VERSION 5.7 ;
BUSBITCHARS "[]" ;
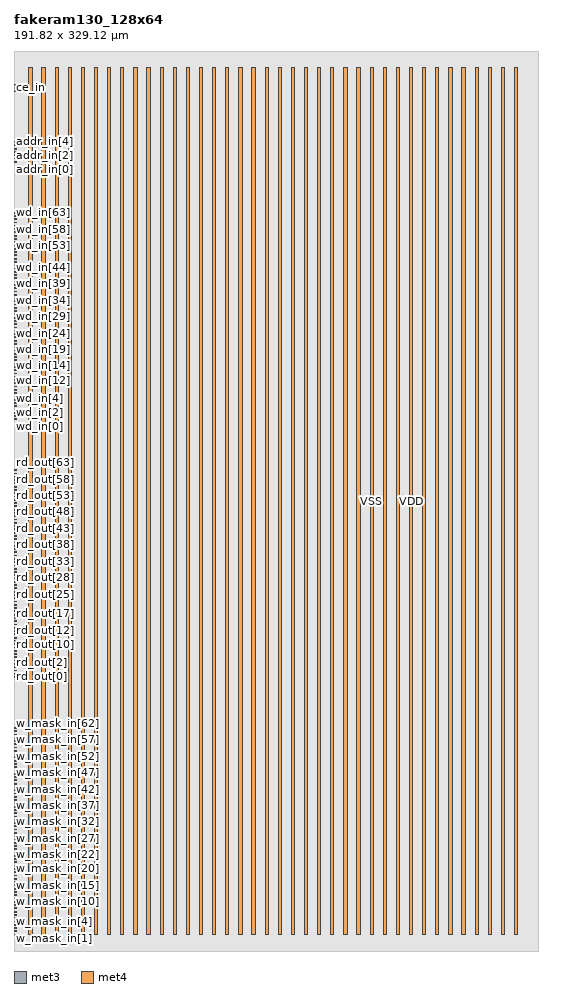
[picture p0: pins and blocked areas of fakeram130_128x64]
MACRO fakeram130_128x64
  FOREIGN fakeram130_128x64 0 0 ;
  SYMMETRY X Y R90 ;
  SIZE 191.820 BY 329.120 ;
  CLASS BLOCK ;
  PIN w_mask_in[0]
    DIRECTION INPUT ;
    USE SIGNAL ;
    SHAPE ABUTMENT ;
    PORT
      LAYER met3 ;
      RECT 0.000 5.850 0.800 6.150 ;
    END
  END w_mask_in[0]
  PIN w_mask_in[1]
    DIRECTION INPUT ;
    USE SIGNAL ;
    SHAPE ABUTMENT ;
    PORT
      LAYER met3 ;
      RECT 0.000 7.050 0.800 7.350 ;
    END
  END w_mask_in[1]
  PIN w_mask_in[2]
    DIRECTION INPUT ;
    USE SIGNAL ;
    SHAPE ABUTMENT ;
    PORT
      LAYER met3 ;
      RECT 0.000 8.250 0.800 8.550 ;
    END
  END w_mask_in[2]
  PIN w_mask_in[3]
    DIRECTION INPUT ;
    USE SIGNAL ;
    SHAPE ABUTMENT ;
    PORT
      LAYER met3 ;
      RECT 0.000 9.450 0.800 9.750 ;
    END
  END w_mask_in[3]
  PIN w_mask_in[4]
    DIRECTION INPUT ;
    USE SIGNAL ;
    SHAPE ABUTMENT ;
    PORT
      LAYER met3 ;
      RECT 0.000 10.650 0.800 10.950 ;
    END
  END w_mask_in[4]
  PIN w_mask_in[5]
    DIRECTION INPUT ;
    USE SIGNAL ;
    SHAPE ABUTMENT ;
    PORT
      LAYER met3 ;
      RECT 0.000 11.850 0.800 12.150 ;
    END
  END w_mask_in[5]
  PIN w_mask_in[6]
    DIRECTION INPUT ;
    USE SIGNAL ;
    SHAPE ABUTMENT ;
    PORT
      LAYER met3 ;
      RECT 0.000 13.050 0.800 13.350 ;
    END
  END w_mask_in[6]
  PIN w_mask_in[7]
    DIRECTION INPUT ;
    USE SIGNAL ;
    SHAPE ABUTMENT ;
    PORT
      LAYER met3 ;
      RECT 0.000 14.250 0.800 14.550 ;
    END
  END w_mask_in[7]
  PIN w_mask_in[8]
    DIRECTION INPUT ;
    USE SIGNAL ;
    SHAPE ABUTMENT ;
    PORT
      LAYER met3 ;
      RECT 0.000 15.450 0.800 15.750 ;
    END
  END w_mask_in[8]
  PIN w_mask_in[9]
    DIRECTION INPUT ;
    USE SIGNAL ;
    SHAPE ABUTMENT ;
    PORT
      LAYER met3 ;
      RECT 0.000 16.650 0.800 16.950 ;
    END
  END w_mask_in[9]
  PIN w_mask_in[10]
    DIRECTION INPUT ;
    USE SIGNAL ;
    SHAPE ABUTMENT ;
    PORT
      LAYER met3 ;
      RECT 0.000 17.850 0.800 18.150 ;
    END
  END w_mask_in[10]
  PIN w_mask_in[11]
    DIRECTION INPUT ;
    USE SIGNAL ;
    SHAPE ABUTMENT ;
    PORT
      LAYER met3 ;
      RECT 0.000 19.050 0.800 19.350 ;
    END
  END w_mask_in[11]
  PIN w_mask_in[12]
    DIRECTION INPUT ;
    USE SIGNAL ;
    SHAPE ABUTMENT ;
    PORT
      LAYER met3 ;
      RECT 0.000 20.250 0.800 20.550 ;
    END
  END w_mask_in[12]
  PIN w_mask_in[13]
    DIRECTION INPUT ;
    USE SIGNAL ;
    SHAPE ABUTMENT ;
    PORT
      LAYER met3 ;
      RECT 0.000 21.450 0.800 21.750 ;
    END
  END w_mask_in[13]
  PIN w_mask_in[14]
    DIRECTION INPUT ;
    USE SIGNAL ;
    SHAPE ABUTMENT ;
    PORT
      LAYER met3 ;
      RECT 0.000 22.650 0.800 22.950 ;
    END
  END w_mask_in[14]
  PIN w_mask_in[15]
    DIRECTION INPUT ;
    USE SIGNAL ;
    SHAPE ABUTMENT ;
    PORT
      LAYER met3 ;
      RECT 0.000 23.850 0.800 24.150 ;
    END
  END w_mask_in[15]
  PIN w_mask_in[16]
    DIRECTION INPUT ;
    USE SIGNAL ;
    SHAPE ABUTMENT ;
    PORT
      LAYER met3 ;
      RECT 0.000 25.050 0.800 25.350 ;
    END
  END w_mask_in[16]
  PIN w_mask_in[17]
    DIRECTION INPUT ;
    USE SIGNAL ;
    SHAPE ABUTMENT ;
    PORT
      LAYER met3 ;
      RECT 0.000 26.250 0.800 26.550 ;
    END
  END w_mask_in[17]
  PIN w_mask_in[18]
    DIRECTION INPUT ;
    USE SIGNAL ;
    SHAPE ABUTMENT ;
    PORT
      LAYER met3 ;
      RECT 0.000 27.450 0.800 27.750 ;
    END
  END w_mask_in[18]
  PIN w_mask_in[19]
    DIRECTION INPUT ;
    USE SIGNAL ;
    SHAPE ABUTMENT ;
    PORT
      LAYER met3 ;
      RECT 0.000 28.650 0.800 28.950 ;
    END
  END w_mask_in[19]
  PIN w_mask_in[20]
    DIRECTION INPUT ;
    USE SIGNAL ;
    SHAPE ABUTMENT ;
    PORT
      LAYER met3 ;
      RECT 0.000 29.850 0.800 30.150 ;
    END
  END w_mask_in[20]
  PIN w_mask_in[21]
    DIRECTION INPUT ;
    USE SIGNAL ;
    SHAPE ABUTMENT ;
    PORT
      LAYER met3 ;
      RECT 0.000 31.050 0.800 31.350 ;
    END
  END w_mask_in[21]
  PIN w_mask_in[22]
    DIRECTION INPUT ;
    USE SIGNAL ;
    SHAPE ABUTMENT ;
    PORT
      LAYER met3 ;
      RECT 0.000 32.250 0.800 32.550 ;
    END
  END w_mask_in[22]
  PIN w_mask_in[23]
    DIRECTION INPUT ;
    USE SIGNAL ;
    SHAPE ABUTMENT ;
    PORT
      LAYER met3 ;
      RECT 0.000 33.450 0.800 33.750 ;
    END
  END w_mask_in[23]
  PIN w_mask_in[24]
    DIRECTION INPUT ;
    USE SIGNAL ;
    SHAPE ABUTMENT ;
    PORT
      LAYER met3 ;
      RECT 0.000 34.650 0.800 34.950 ;
    END
  END w_mask_in[24]
  PIN w_mask_in[25]
    DIRECTION INPUT ;
    USE SIGNAL ;
    SHAPE ABUTMENT ;
    PORT
      LAYER met3 ;
      RECT 0.000 35.850 0.800 36.150 ;
    END
  END w_mask_in[25]
  PIN w_mask_in[26]
    DIRECTION INPUT ;
    USE SIGNAL ;
    SHAPE ABUTMENT ;
    PORT
      LAYER met3 ;
      RECT 0.000 37.050 0.800 37.350 ;
    END
  END w_mask_in[26]
  PIN w_mask_in[27]
    DIRECTION INPUT ;
    USE SIGNAL ;
    SHAPE ABUTMENT ;
    PORT
      LAYER met3 ;
      RECT 0.000 38.250 0.800 38.550 ;
    END
  END w_mask_in[27]
  PIN w_mask_in[28]
    DIRECTION INPUT ;
    USE SIGNAL ;
    SHAPE ABUTMENT ;
    PORT
      LAYER met3 ;
      RECT 0.000 39.450 0.800 39.750 ;
    END
  END w_mask_in[28]
  PIN w_mask_in[29]
    DIRECTION INPUT ;
    USE SIGNAL ;
    SHAPE ABUTMENT ;
    PORT
      LAYER met3 ;
      RECT 0.000 40.650 0.800 40.950 ;
    END
  END w_mask_in[29]
  PIN w_mask_in[30]
    DIRECTION INPUT ;
    USE SIGNAL ;
    SHAPE ABUTMENT ;
    PORT
      LAYER met3 ;
      RECT 0.000 41.850 0.800 42.150 ;
    END
  END w_mask_in[30]
  PIN w_mask_in[31]
    DIRECTION INPUT ;
    USE SIGNAL ;
    SHAPE ABUTMENT ;
    PORT
      LAYER met3 ;
      RECT 0.000 43.050 0.800 43.350 ;
    END
  END w_mask_in[31]
  PIN w_mask_in[32]
    DIRECTION INPUT ;
    USE SIGNAL ;
    SHAPE ABUTMENT ;
    PORT
      LAYER met3 ;
      RECT 0.000 44.250 0.800 44.550 ;
    END
  END w_mask_in[32]
  PIN w_mask_in[33]
    DIRECTION INPUT ;
    USE SIGNAL ;
    SHAPE ABUTMENT ;
    PORT
      LAYER met3 ;
      RECT 0.000 45.450 0.800 45.750 ;
    END
  END w_mask_in[33]
  PIN w_mask_in[34]
    DIRECTION INPUT ;
    USE SIGNAL ;
    SHAPE ABUTMENT ;
    PORT
      LAYER met3 ;
      RECT 0.000 46.650 0.800 46.950 ;
    END
  END w_mask_in[34]
  PIN w_mask_in[35]
    DIRECTION INPUT ;
    USE SIGNAL ;
    SHAPE ABUTMENT ;
    PORT
      LAYER met3 ;
      RECT 0.000 47.850 0.800 48.150 ;
    END
  END w_mask_in[35]
  PIN w_mask_in[36]
    DIRECTION INPUT ;
    USE SIGNAL ;
    SHAPE ABUTMENT ;
    PORT
      LAYER met3 ;
      RECT 0.000 49.050 0.800 49.350 ;
    END
  END w_mask_in[36]
  PIN w_mask_in[37]
    DIRECTION INPUT ;
    USE SIGNAL ;
    SHAPE ABUTMENT ;
    PORT
      LAYER met3 ;
      RECT 0.000 50.250 0.800 50.550 ;
    END
  END w_mask_in[37]
  PIN w_mask_in[38]
    DIRECTION INPUT ;
    USE SIGNAL ;
    SHAPE ABUTMENT ;
    PORT
      LAYER met3 ;
      RECT 0.000 51.450 0.800 51.750 ;
    END
  END w_mask_in[38]
  PIN w_mask_in[39]
    DIRECTION INPUT ;
    USE SIGNAL ;
    SHAPE ABUTMENT ;
    PORT
      LAYER met3 ;
      RECT 0.000 52.650 0.800 52.950 ;
    END
  END w_mask_in[39]
  PIN w_mask_in[40]
    DIRECTION INPUT ;
    USE SIGNAL ;
    SHAPE ABUTMENT ;
    PORT
      LAYER met3 ;
      RECT 0.000 53.850 0.800 54.150 ;
    END
  END w_mask_in[40]
  PIN w_mask_in[41]
    DIRECTION INPUT ;
    USE SIGNAL ;
    SHAPE ABUTMENT ;
    PORT
      LAYER met3 ;
      RECT 0.000 55.050 0.800 55.350 ;
    END
  END w_mask_in[41]
  PIN w_mask_in[42]
    DIRECTION INPUT ;
    USE SIGNAL ;
    SHAPE ABUTMENT ;
    PORT
      LAYER met3 ;
      RECT 0.000 56.250 0.800 56.550 ;
    END
  END w_mask_in[42]
  PIN w_mask_in[43]
    DIRECTION INPUT ;
    USE SIGNAL ;
    SHAPE ABUTMENT ;
    PORT
      LAYER met3 ;
      RECT 0.000 57.450 0.800 57.750 ;
    END
  END w_mask_in[43]
  PIN w_mask_in[44]
    DIRECTION INPUT ;
    USE SIGNAL ;
    SHAPE ABUTMENT ;
    PORT
      LAYER met3 ;
      RECT 0.000 58.650 0.800 58.950 ;
    END
  END w_mask_in[44]
  PIN w_mask_in[45]
    DIRECTION INPUT ;
    USE SIGNAL ;
    SHAPE ABUTMENT ;
    PORT
      LAYER met3 ;
      RECT 0.000 59.850 0.800 60.150 ;
    END
  END w_mask_in[45]
  PIN w_mask_in[46]
    DIRECTION INPUT ;
    USE SIGNAL ;
    SHAPE ABUTMENT ;
    PORT
      LAYER met3 ;
      RECT 0.000 61.050 0.800 61.350 ;
    END
  END w_mask_in[46]
  PIN w_mask_in[47]
    DIRECTION INPUT ;
    USE SIGNAL ;
    SHAPE ABUTMENT ;
    PORT
      LAYER met3 ;
      RECT 0.000 62.250 0.800 62.550 ;
    END
  END w_mask_in[47]
  PIN w_mask_in[48]
    DIRECTION INPUT ;
    USE SIGNAL ;
    SHAPE ABUTMENT ;
    PORT
      LAYER met3 ;
      RECT 0.000 63.450 0.800 63.750 ;
    END
  END w_mask_in[48]
  PIN w_mask_in[49]
    DIRECTION INPUT ;
    USE SIGNAL ;
    SHAPE ABUTMENT ;
    PORT
      LAYER met3 ;
      RECT 0.000 64.650 0.800 64.950 ;
    END
  END w_mask_in[49]
  PIN w_mask_in[50]
    DIRECTION INPUT ;
    USE SIGNAL ;
    SHAPE ABUTMENT ;
    PORT
      LAYER met3 ;
      RECT 0.000 65.850 0.800 66.150 ;
    END
  END w_mask_in[50]
  PIN w_mask_in[51]
    DIRECTION INPUT ;
    USE SIGNAL ;
    SHAPE ABUTMENT ;
    PORT
      LAYER met3 ;
      RECT 0.000 67.050 0.800 67.350 ;
    END
  END w_mask_in[51]
  PIN w_mask_in[52]
    DIRECTION INPUT ;
    USE SIGNAL ;
    SHAPE ABUTMENT ;
    PORT
      LAYER met3 ;
      RECT 0.000 68.250 0.800 68.550 ;
    END
  END w_mask_in[52]
  PIN w_mask_in[53]
    DIRECTION INPUT ;
    USE SIGNAL ;
    SHAPE ABUTMENT ;
    PORT
      LAYER met3 ;
      RECT 0.000 69.450 0.800 69.750 ;
    END
  END w_mask_in[53]
  PIN w_mask_in[54]
    DIRECTION INPUT ;
    USE SIGNAL ;
    SHAPE ABUTMENT ;
    PORT
      LAYER met3 ;
      RECT 0.000 70.650 0.800 70.950 ;
    END
  END w_mask_in[54]
  PIN w_mask_in[55]
    DIRECTION INPUT ;
    USE SIGNAL ;
    SHAPE ABUTMENT ;
    PORT
      LAYER met3 ;
      RECT 0.000 71.850 0.800 72.150 ;
    END
  END w_mask_in[55]
  PIN w_mask_in[56]
    DIRECTION INPUT ;
    USE SIGNAL ;
    SHAPE ABUTMENT ;
    PORT
      LAYER met3 ;
      RECT 0.000 73.050 0.800 73.350 ;
    END
  END w_mask_in[56]
  PIN w_mask_in[57]
    DIRECTION INPUT ;
    USE SIGNAL ;
    SHAPE ABUTMENT ;
    PORT
      LAYER met3 ;
      RECT 0.000 74.250 0.800 74.550 ;
    END
  END w_mask_in[57]
  PIN w_mask_in[58]
    DIRECTION INPUT ;
    USE SIGNAL ;
    SHAPE ABUTMENT ;
    PORT
      LAYER met3 ;
      RECT 0.000 75.450 0.800 75.750 ;
    END
  END w_mask_in[58]
  PIN w_mask_in[59]
    DIRECTION INPUT ;
    USE SIGNAL ;
    SHAPE ABUTMENT ;
    PORT
      LAYER met3 ;
      RECT 0.000 76.650 0.800 76.950 ;
    END
  END w_mask_in[59]
  PIN w_mask_in[60]
    DIRECTION INPUT ;
    USE SIGNAL ;
    SHAPE ABUTMENT ;
    PORT
      LAYER met3 ;
      RECT 0.000 77.850 0.800 78.150 ;
    END
  END w_mask_in[60]
  PIN w_mask_in[61]
    DIRECTION INPUT ;
    USE SIGNAL ;
    SHAPE ABUTMENT ;
    PORT
      LAYER met3 ;
      RECT 0.000 79.050 0.800 79.350 ;
    END
  END w_mask_in[61]
  PIN w_mask_in[62]
    DIRECTION INPUT ;
    USE SIGNAL ;
    SHAPE ABUTMENT ;
    PORT
      LAYER met3 ;
      RECT 0.000 80.250 0.800 80.550 ;
    END
  END w_mask_in[62]
  PIN w_mask_in[63]
    DIRECTION INPUT ;
    USE SIGNAL ;
    SHAPE ABUTMENT ;
    PORT
      LAYER met3 ;
      RECT 0.000 81.450 0.800 81.750 ;
    END
  END w_mask_in[63]
  PIN rd_out[0]
    DIRECTION OUTPUT ;
    USE SIGNAL ;
    SHAPE ABUTMENT ;
    PORT
      LAYER met3 ;
      RECT 0.000 100.050 0.800 100.350 ;
    END
  END rd_out[0]
  PIN rd_out[1]
    DIRECTION OUTPUT ;
    USE SIGNAL ;
    SHAPE ABUTMENT ;
    PORT
      LAYER met3 ;
      RECT 0.000 101.250 0.800 101.550 ;
    END
  END rd_out[1]
  PIN rd_out[2]
    DIRECTION OUTPUT ;
    USE SIGNAL ;
    SHAPE ABUTMENT ;
    PORT
      LAYER met3 ;
      RECT 0.000 102.450 0.800 102.750 ;
    END
  END rd_out[2]
  PIN rd_out[3]
    DIRECTION OUTPUT ;
    USE SIGNAL ;
    SHAPE ABUTMENT ;
    PORT
      LAYER met3 ;
      RECT 0.000 103.650 0.800 103.950 ;
    END
  END rd_out[3]
  PIN rd_out[4]
    DIRECTION OUTPUT ;
    USE SIGNAL ;
    SHAPE ABUTMENT ;
    PORT
      LAYER met3 ;
      RECT 0.000 104.850 0.800 105.150 ;
    END
  END rd_out[4]
  PIN rd_out[5]
    DIRECTION OUTPUT ;
    USE SIGNAL ;
    SHAPE ABUTMENT ;
    PORT
      LAYER met3 ;
      RECT 0.000 106.050 0.800 106.350 ;
    END
  END rd_out[5]
  PIN rd_out[6]
    DIRECTION OUTPUT ;
    USE SIGNAL ;
    SHAPE ABUTMENT ;
    PORT
      LAYER met3 ;
      RECT 0.000 107.250 0.800 107.550 ;
    END
  END rd_out[6]
  PIN rd_out[7]
    DIRECTION OUTPUT ;
    USE SIGNAL ;
    SHAPE ABUTMENT ;
    PORT
      LAYER met3 ;
      RECT 0.000 108.450 0.800 108.750 ;
    END
  END rd_out[7]
  PIN rd_out[8]
    DIRECTION OUTPUT ;
    USE SIGNAL ;
    SHAPE ABUTMENT ;
    PORT
      LAYER met3 ;
      RECT 0.000 109.650 0.800 109.950 ;
    END
  END rd_out[8]
  PIN rd_out[9]
    DIRECTION OUTPUT ;
    USE SIGNAL ;
    SHAPE ABUTMENT ;
    PORT
      LAYER met3 ;
      RECT 0.000 110.850 0.800 111.150 ;
    END
  END rd_out[9]
  PIN rd_out[10]
    DIRECTION OUTPUT ;
    USE SIGNAL ;
    SHAPE ABUTMENT ;
    PORT
      LAYER met3 ;
      RECT 0.000 112.050 0.800 112.350 ;
    END
  END rd_out[10]
  PIN rd_out[11]
    DIRECTION OUTPUT ;
    USE SIGNAL ;
    SHAPE ABUTMENT ;
    PORT
      LAYER met3 ;
      RECT 0.000 113.250 0.800 113.550 ;
    END
  END rd_out[11]
  PIN rd_out[12]
    DIRECTION OUTPUT ;
    USE SIGNAL ;
    SHAPE ABUTMENT ;
    PORT
      LAYER met3 ;
      RECT 0.000 114.450 0.800 114.750 ;
    END
  END rd_out[12]
  PIN rd_out[13]
    DIRECTION OUTPUT ;
    USE SIGNAL ;
    SHAPE ABUTMENT ;
    PORT
      LAYER met3 ;
      RECT 0.000 115.650 0.800 115.950 ;
    END
  END rd_out[13]
  PIN rd_out[14]
    DIRECTION OUTPUT ;
    USE SIGNAL ;
    SHAPE ABUTMENT ;
    PORT
      LAYER met3 ;
      RECT 0.000 116.850 0.800 117.150 ;
    END
  END rd_out[14]
  PIN rd_out[15]
    DIRECTION OUTPUT ;
    USE SIGNAL ;
    SHAPE ABUTMENT ;
    PORT
      LAYER met3 ;
      RECT 0.000 118.050 0.800 118.350 ;
    END
  END rd_out[15]
  PIN rd_out[16]
    DIRECTION OUTPUT ;
    USE SIGNAL ;
    SHAPE ABUTMENT ;
    PORT
      LAYER met3 ;
      RECT 0.000 119.250 0.800 119.550 ;
    END
  END rd_out[16]
  PIN rd_out[17]
    DIRECTION OUTPUT ;
    USE SIGNAL ;
    SHAPE ABUTMENT ;
    PORT
      LAYER met3 ;
      RECT 0.000 120.450 0.800 120.750 ;
    END
  END rd_out[17]
  PIN rd_out[18]
    DIRECTION OUTPUT ;
    USE SIGNAL ;
    SHAPE ABUTMENT ;
    PORT
      LAYER met3 ;
      RECT 0.000 121.650 0.800 121.950 ;
    END
  END rd_out[18]
  PIN rd_out[19]
    DIRECTION OUTPUT ;
    USE SIGNAL ;
    SHAPE ABUTMENT ;
    PORT
      LAYER met3 ;
      RECT 0.000 122.850 0.800 123.150 ;
    END
  END rd_out[19]
  PIN rd_out[20]
    DIRECTION OUTPUT ;
    USE SIGNAL ;
    SHAPE ABUTMENT ;
    PORT
      LAYER met3 ;
      RECT 0.000 124.050 0.800 124.350 ;
    END
  END rd_out[20]
  PIN rd_out[21]
    DIRECTION OUTPUT ;
    USE SIGNAL ;
    SHAPE ABUTMENT ;
    PORT
      LAYER met3 ;
      RECT 0.000 125.250 0.800 125.550 ;
    END
  END rd_out[21]
  PIN rd_out[22]
    DIRECTION OUTPUT ;
    USE SIGNAL ;
    SHAPE ABUTMENT ;
    PORT
      LAYER met3 ;
      RECT 0.000 126.450 0.800 126.750 ;
    END
  END rd_out[22]
  PIN rd_out[23]
    DIRECTION OUTPUT ;
    USE SIGNAL ;
    SHAPE ABUTMENT ;
    PORT
      LAYER met3 ;
      RECT 0.000 127.650 0.800 127.950 ;
    END
  END rd_out[23]
  PIN rd_out[24]
    DIRECTION OUTPUT ;
    USE SIGNAL ;
    SHAPE ABUTMENT ;
    PORT
      LAYER met3 ;
      RECT 0.000 128.850 0.800 129.150 ;
    END
  END rd_out[24]
  PIN rd_out[25]
    DIRECTION OUTPUT ;
    USE SIGNAL ;
    SHAPE ABUTMENT ;
    PORT
      LAYER met3 ;
      RECT 0.000 130.050 0.800 130.350 ;
    END
  END rd_out[25]
  PIN rd_out[26]
    DIRECTION OUTPUT ;
    USE SIGNAL ;
    SHAPE ABUTMENT ;
    PORT
      LAYER met3 ;
      RECT 0.000 131.250 0.800 131.550 ;
    END
  END rd_out[26]
  PIN rd_out[27]
    DIRECTION OUTPUT ;
    USE SIGNAL ;
    SHAPE ABUTMENT ;
    PORT
      LAYER met3 ;
      RECT 0.000 132.450 0.800 132.750 ;
    END
  END rd_out[27]
  PIN rd_out[28]
    DIRECTION OUTPUT ;
    USE SIGNAL ;
    SHAPE ABUTMENT ;
    PORT
      LAYER met3 ;
      RECT 0.000 133.650 0.800 133.950 ;
    END
  END rd_out[28]
  PIN rd_out[29]
    DIRECTION OUTPUT ;
    USE SIGNAL ;
    SHAPE ABUTMENT ;
    PORT
      LAYER met3 ;
      RECT 0.000 134.850 0.800 135.150 ;
    END
  END rd_out[29]
  PIN rd_out[30]
    DIRECTION OUTPUT ;
    USE SIGNAL ;
    SHAPE ABUTMENT ;
    PORT
      LAYER met3 ;
      RECT 0.000 136.050 0.800 136.350 ;
    END
  END rd_out[30]
  PIN rd_out[31]
    DIRECTION OUTPUT ;
    USE SIGNAL ;
    SHAPE ABUTMENT ;
    PORT
      LAYER met3 ;
      RECT 0.000 137.250 0.800 137.550 ;
    END
  END rd_out[31]
  PIN rd_out[32]
    DIRECTION OUTPUT ;
    USE SIGNAL ;
    SHAPE ABUTMENT ;
    PORT
      LAYER met3 ;
      RECT 0.000 138.450 0.800 138.750 ;
    END
  END rd_out[32]
  PIN rd_out[33]
    DIRECTION OUTPUT ;
    USE SIGNAL ;
    SHAPE ABUTMENT ;
    PORT
      LAYER met3 ;
      RECT 0.000 139.650 0.800 139.950 ;
    END
  END rd_out[33]
  PIN rd_out[34]
    DIRECTION OUTPUT ;
    USE SIGNAL ;
    SHAPE ABUTMENT ;
    PORT
      LAYER met3 ;
      RECT 0.000 140.850 0.800 141.150 ;
    END
  END rd_out[34]
  PIN rd_out[35]
    DIRECTION OUTPUT ;
    USE SIGNAL ;
    SHAPE ABUTMENT ;
    PORT
      LAYER met3 ;
      RECT 0.000 142.050 0.800 142.350 ;
    END
  END rd_out[35]
  PIN rd_out[36]
    DIRECTION OUTPUT ;
    USE SIGNAL ;
    SHAPE ABUTMENT ;
    PORT
      LAYER met3 ;
      RECT 0.000 143.250 0.800 143.550 ;
    END
  END rd_out[36]
  PIN rd_out[37]
    DIRECTION OUTPUT ;
    USE SIGNAL ;
    SHAPE ABUTMENT ;
    PORT
      LAYER met3 ;
      RECT 0.000 144.450 0.800 144.750 ;
    END
  END rd_out[37]
  PIN rd_out[38]
    DIRECTION OUTPUT ;
    USE SIGNAL ;
    SHAPE ABUTMENT ;
    PORT
      LAYER met3 ;
      RECT 0.000 145.650 0.800 145.950 ;
    END
  END rd_out[38]
  PIN rd_out[39]
    DIRECTION OUTPUT ;
    USE SIGNAL ;
    SHAPE ABUTMENT ;
    PORT
      LAYER met3 ;
      RECT 0.000 146.850 0.800 147.150 ;
    END
  END rd_out[39]
  PIN rd_out[40]
    DIRECTION OUTPUT ;
    USE SIGNAL ;
    SHAPE ABUTMENT ;
    PORT
      LAYER met3 ;
      RECT 0.000 148.050 0.800 148.350 ;
    END
  END rd_out[40]
  PIN rd_out[41]
    DIRECTION OUTPUT ;
    USE SIGNAL ;
    SHAPE ABUTMENT ;
    PORT
      LAYER met3 ;
      RECT 0.000 149.250 0.800 149.550 ;
    END
  END rd_out[41]
  PIN rd_out[42]
    DIRECTION OUTPUT ;
    USE SIGNAL ;
    SHAPE ABUTMENT ;
    PORT
      LAYER met3 ;
      RECT 0.000 150.450 0.800 150.750 ;
    END
  END rd_out[42]
  PIN rd_out[43]
    DIRECTION OUTPUT ;
    USE SIGNAL ;
    SHAPE ABUTMENT ;
    PORT
      LAYER met3 ;
      RECT 0.000 151.650 0.800 151.950 ;
    END
  END rd_out[43]
  PIN rd_out[44]
    DIRECTION OUTPUT ;
    USE SIGNAL ;
    SHAPE ABUTMENT ;
    PORT
      LAYER met3 ;
      RECT 0.000 152.850 0.800 153.150 ;
    END
  END rd_out[44]
  PIN rd_out[45]
    DIRECTION OUTPUT ;
    USE SIGNAL ;
    SHAPE ABUTMENT ;
    PORT
      LAYER met3 ;
      RECT 0.000 154.050 0.800 154.350 ;
    END
  END rd_out[45]
  PIN rd_out[46]
    DIRECTION OUTPUT ;
    USE SIGNAL ;
    SHAPE ABUTMENT ;
    PORT
      LAYER met3 ;
      RECT 0.000 155.250 0.800 155.550 ;
    END
  END rd_out[46]
  PIN rd_out[47]
    DIRECTION OUTPUT ;
    USE SIGNAL ;
    SHAPE ABUTMENT ;
    PORT
      LAYER met3 ;
      RECT 0.000 156.450 0.800 156.750 ;
    END
  END rd_out[47]
  PIN rd_out[48]
    DIRECTION OUTPUT ;
    USE SIGNAL ;
    SHAPE ABUTMENT ;
    PORT
      LAYER met3 ;
      RECT 0.000 157.650 0.800 157.950 ;
    END
  END rd_out[48]
  PIN rd_out[49]
    DIRECTION OUTPUT ;
    USE SIGNAL ;
    SHAPE ABUTMENT ;
    PORT
      LAYER met3 ;
      RECT 0.000 158.850 0.800 159.150 ;
    END
  END rd_out[49]
  PIN rd_out[50]
    DIRECTION OUTPUT ;
    USE SIGNAL ;
    SHAPE ABUTMENT ;
    PORT
      LAYER met3 ;
      RECT 0.000 160.050 0.800 160.350 ;
    END
  END rd_out[50]
  PIN rd_out[51]
    DIRECTION OUTPUT ;
    USE SIGNAL ;
    SHAPE ABUTMENT ;
    PORT
      LAYER met3 ;
      RECT 0.000 161.250 0.800 161.550 ;
    END
  END rd_out[51]
  PIN rd_out[52]
    DIRECTION OUTPUT ;
    USE SIGNAL ;
    SHAPE ABUTMENT ;
    PORT
      LAYER met3 ;
      RECT 0.000 162.450 0.800 162.750 ;
    END
  END rd_out[52]
  PIN rd_out[53]
    DIRECTION OUTPUT ;
    USE SIGNAL ;
    SHAPE ABUTMENT ;
    PORT
      LAYER met3 ;
      RECT 0.000 163.650 0.800 163.950 ;
    END
  END rd_out[53]
  PIN rd_out[54]
    DIRECTION OUTPUT ;
    USE SIGNAL ;
    SHAPE ABUTMENT ;
    PORT
      LAYER met3 ;
      RECT 0.000 164.850 0.800 165.150 ;
    END
  END rd_out[54]
  PIN rd_out[55]
    DIRECTION OUTPUT ;
    USE SIGNAL ;
    SHAPE ABUTMENT ;
    PORT
      LAYER met3 ;
      RECT 0.000 166.050 0.800 166.350 ;
    END
  END rd_out[55]
  PIN rd_out[56]
    DIRECTION OUTPUT ;
    USE SIGNAL ;
    SHAPE ABUTMENT ;
    PORT
      LAYER met3 ;
      RECT 0.000 167.250 0.800 167.550 ;
    END
  END rd_out[56]
  PIN rd_out[57]
    DIRECTION OUTPUT ;
    USE SIGNAL ;
    SHAPE ABUTMENT ;
    PORT
      LAYER met3 ;
      RECT 0.000 168.450 0.800 168.750 ;
    END
  END rd_out[57]
  PIN rd_out[58]
    DIRECTION OUTPUT ;
    USE SIGNAL ;
    SHAPE ABUTMENT ;
    PORT
      LAYER met3 ;
      RECT 0.000 169.650 0.800 169.950 ;
    END
  END rd_out[58]
  PIN rd_out[59]
    DIRECTION OUTPUT ;
    USE SIGNAL ;
    SHAPE ABUTMENT ;
    PORT
      LAYER met3 ;
      RECT 0.000 170.850 0.800 171.150 ;
    END
  END rd_out[59]
  PIN rd_out[60]
    DIRECTION OUTPUT ;
    USE SIGNAL ;
    SHAPE ABUTMENT ;
    PORT
      LAYER met3 ;
      RECT 0.000 172.050 0.800 172.350 ;
    END
  END rd_out[60]
  PIN rd_out[61]
    DIRECTION OUTPUT ;
    USE SIGNAL ;
    SHAPE ABUTMENT ;
    PORT
      LAYER met3 ;
      RECT 0.000 173.250 0.800 173.550 ;
    END
  END rd_out[61]
  PIN rd_out[62]
    DIRECTION OUTPUT ;
    USE SIGNAL ;
    SHAPE ABUTMENT ;
    PORT
      LAYER met3 ;
      RECT 0.000 174.450 0.800 174.750 ;
    END
  END rd_out[62]
  PIN rd_out[63]
    DIRECTION OUTPUT ;
    USE SIGNAL ;
    SHAPE ABUTMENT ;
    PORT
      LAYER met3 ;
      RECT 0.000 175.650 0.800 175.950 ;
    END
  END rd_out[63]
  PIN wd_in[0]
    DIRECTION INPUT ;
    USE SIGNAL ;
    SHAPE ABUTMENT ;
    PORT
      LAYER met3 ;
      RECT 0.000 194.250 0.800 194.550 ;
    END
  END wd_in[0]
  PIN wd_in[1]
    DIRECTION INPUT ;
    USE SIGNAL ;
    SHAPE ABUTMENT ;
    PORT
      LAYER met3 ;
      RECT 0.000 195.450 0.800 195.750 ;
    END
  END wd_in[1]
  PIN wd_in[2]
    DIRECTION INPUT ;
    USE SIGNAL ;
    SHAPE ABUTMENT ;
    PORT
      LAYER met3 ;
      RECT 0.000 196.650 0.800 196.950 ;
    END
  END wd_in[2]
  PIN wd_in[3]
    DIRECTION INPUT ;
    USE SIGNAL ;
    SHAPE ABUTMENT ;
    PORT
      LAYER met3 ;
      RECT 0.000 197.850 0.800 198.150 ;
    END
  END wd_in[3]
  PIN wd_in[4]
    DIRECTION INPUT ;
    USE SIGNAL ;
    SHAPE ABUTMENT ;
    PORT
      LAYER met3 ;
      RECT 0.000 199.050 0.800 199.350 ;
    END
  END wd_in[4]
  PIN wd_in[5]
    DIRECTION INPUT ;
    USE SIGNAL ;
    SHAPE ABUTMENT ;
    PORT
      LAYER met3 ;
      RECT 0.000 200.250 0.800 200.550 ;
    END
  END wd_in[5]
  PIN wd_in[6]
    DIRECTION INPUT ;
    USE SIGNAL ;
    SHAPE ABUTMENT ;
    PORT
      LAYER met3 ;
      RECT 0.000 201.450 0.800 201.750 ;
    END
  END wd_in[6]
  PIN wd_in[7]
    DIRECTION INPUT ;
    USE SIGNAL ;
    SHAPE ABUTMENT ;
    PORT
      LAYER met3 ;
      RECT 0.000 202.650 0.800 202.950 ;
    END
  END wd_in[7]
  PIN wd_in[8]
    DIRECTION INPUT ;
    USE SIGNAL ;
    SHAPE ABUTMENT ;
    PORT
      LAYER met3 ;
      RECT 0.000 203.850 0.800 204.150 ;
    END
  END wd_in[8]
  PIN wd_in[9]
    DIRECTION INPUT ;
    USE SIGNAL ;
    SHAPE ABUTMENT ;
    PORT
      LAYER met3 ;
      RECT 0.000 205.050 0.800 205.350 ;
    END
  END wd_in[9]
  PIN wd_in[10]
    DIRECTION INPUT ;
    USE SIGNAL ;
    SHAPE ABUTMENT ;
    PORT
      LAYER met3 ;
      RECT 0.000 206.250 0.800 206.550 ;
    END
  END wd_in[10]
  PIN wd_in[11]
    DIRECTION INPUT ;
    USE SIGNAL ;
    SHAPE ABUTMENT ;
    PORT
      LAYER met3 ;
      RECT 0.000 207.450 0.800 207.750 ;
    END
  END wd_in[11]
  PIN wd_in[12]
    DIRECTION INPUT ;
    USE SIGNAL ;
    SHAPE ABUTMENT ;
    PORT
      LAYER met3 ;
      RECT 0.000 208.650 0.800 208.950 ;
    END
  END wd_in[12]
  PIN wd_in[13]
    DIRECTION INPUT ;
    USE SIGNAL ;
    SHAPE ABUTMENT ;
    PORT
      LAYER met3 ;
      RECT 0.000 209.850 0.800 210.150 ;
    END
  END wd_in[13]
  PIN wd_in[14]
    DIRECTION INPUT ;
    USE SIGNAL ;
    SHAPE ABUTMENT ;
    PORT
      LAYER met3 ;
      RECT 0.000 211.050 0.800 211.350 ;
    END
  END wd_in[14]
  PIN wd_in[15]
    DIRECTION INPUT ;
    USE SIGNAL ;
    SHAPE ABUTMENT ;
    PORT
      LAYER met3 ;
      RECT 0.000 212.250 0.800 212.550 ;
    END
  END wd_in[15]
  PIN wd_in[16]
    DIRECTION INPUT ;
    USE SIGNAL ;
    SHAPE ABUTMENT ;
    PORT
      LAYER met3 ;
      RECT 0.000 213.450 0.800 213.750 ;
    END
  END wd_in[16]
  PIN wd_in[17]
    DIRECTION INPUT ;
    USE SIGNAL ;
    SHAPE ABUTMENT ;
    PORT
      LAYER met3 ;
      RECT 0.000 214.650 0.800 214.950 ;
    END
  END wd_in[17]
  PIN wd_in[18]
    DIRECTION INPUT ;
    USE SIGNAL ;
    SHAPE ABUTMENT ;
    PORT
      LAYER met3 ;
      RECT 0.000 215.850 0.800 216.150 ;
    END
  END wd_in[18]
  PIN wd_in[19]
    DIRECTION INPUT ;
    USE SIGNAL ;
    SHAPE ABUTMENT ;
    PORT
      LAYER met3 ;
      RECT 0.000 217.050 0.800 217.350 ;
    END
  END wd_in[19]
  PIN wd_in[20]
    DIRECTION INPUT ;
    USE SIGNAL ;
    SHAPE ABUTMENT ;
    PORT
      LAYER met3 ;
      RECT 0.000 218.250 0.800 218.550 ;
    END
  END wd_in[20]
  PIN wd_in[21]
    DIRECTION INPUT ;
    USE SIGNAL ;
    SHAPE ABUTMENT ;
    PORT
      LAYER met3 ;
      RECT 0.000 219.450 0.800 219.750 ;
    END
  END wd_in[21]
  PIN wd_in[22]
    DIRECTION INPUT ;
    USE SIGNAL ;
    SHAPE ABUTMENT ;
    PORT
      LAYER met3 ;
      RECT 0.000 220.650 0.800 220.950 ;
    END
  END wd_in[22]
  PIN wd_in[23]
    DIRECTION INPUT ;
    USE SIGNAL ;
    SHAPE ABUTMENT ;
    PORT
      LAYER met3 ;
      RECT 0.000 221.850 0.800 222.150 ;
    END
  END wd_in[23]
  PIN wd_in[24]
    DIRECTION INPUT ;
    USE SIGNAL ;
    SHAPE ABUTMENT ;
    PORT
      LAYER met3 ;
      RECT 0.000 223.050 0.800 223.350 ;
    END
  END wd_in[24]
  PIN wd_in[25]
    DIRECTION INPUT ;
    USE SIGNAL ;
    SHAPE ABUTMENT ;
    PORT
      LAYER met3 ;
      RECT 0.000 224.250 0.800 224.550 ;
    END
  END wd_in[25]
  PIN wd_in[26]
    DIRECTION INPUT ;
    USE SIGNAL ;
    SHAPE ABUTMENT ;
    PORT
      LAYER met3 ;
      RECT 0.000 225.450 0.800 225.750 ;
    END
  END wd_in[26]
  PIN wd_in[27]
    DIRECTION INPUT ;
    USE SIGNAL ;
    SHAPE ABUTMENT ;
    PORT
      LAYER met3 ;
      RECT 0.000 226.650 0.800 226.950 ;
    END
  END wd_in[27]
  PIN wd_in[28]
    DIRECTION INPUT ;
    USE SIGNAL ;
    SHAPE ABUTMENT ;
    PORT
      LAYER met3 ;
      RECT 0.000 227.850 0.800 228.150 ;
    END
  END wd_in[28]
  PIN wd_in[29]
    DIRECTION INPUT ;
    USE SIGNAL ;
    SHAPE ABUTMENT ;
    PORT
      LAYER met3 ;
      RECT 0.000 229.050 0.800 229.350 ;
    END
  END wd_in[29]
  PIN wd_in[30]
    DIRECTION INPUT ;
    USE SIGNAL ;
    SHAPE ABUTMENT ;
    PORT
      LAYER met3 ;
      RECT 0.000 230.250 0.800 230.550 ;
    END
  END wd_in[30]
  PIN wd_in[31]
    DIRECTION INPUT ;
    USE SIGNAL ;
    SHAPE ABUTMENT ;
    PORT
      LAYER met3 ;
      RECT 0.000 231.450 0.800 231.750 ;
    END
  END wd_in[31]
  PIN wd_in[32]
    DIRECTION INPUT ;
    USE SIGNAL ;
    SHAPE ABUTMENT ;
    PORT
      LAYER met3 ;
      RECT 0.000 232.650 0.800 232.950 ;
    END
  END wd_in[32]
  PIN wd_in[33]
    DIRECTION INPUT ;
    USE SIGNAL ;
    SHAPE ABUTMENT ;
    PORT
      LAYER met3 ;
      RECT 0.000 233.850 0.800 234.150 ;
    END
  END wd_in[33]
  PIN wd_in[34]
    DIRECTION INPUT ;
    USE SIGNAL ;
    SHAPE ABUTMENT ;
    PORT
      LAYER met3 ;
      RECT 0.000 235.050 0.800 235.350 ;
    END
  END wd_in[34]
  PIN wd_in[35]
    DIRECTION INPUT ;
    USE SIGNAL ;
    SHAPE ABUTMENT ;
    PORT
      LAYER met3 ;
      RECT 0.000 236.250 0.800 236.550 ;
    END
  END wd_in[35]
  PIN wd_in[36]
    DIRECTION INPUT ;
    USE SIGNAL ;
    SHAPE ABUTMENT ;
    PORT
      LAYER met3 ;
      RECT 0.000 237.450 0.800 237.750 ;
    END
  END wd_in[36]
  PIN wd_in[37]
    DIRECTION INPUT ;
    USE SIGNAL ;
    SHAPE ABUTMENT ;
    PORT
      LAYER met3 ;
      RECT 0.000 238.650 0.800 238.950 ;
    END
  END wd_in[37]
  PIN wd_in[38]
    DIRECTION INPUT ;
    USE SIGNAL ;
    SHAPE ABUTMENT ;
    PORT
      LAYER met3 ;
      RECT 0.000 239.850 0.800 240.150 ;
    END
  END wd_in[38]
  PIN wd_in[39]
    DIRECTION INPUT ;
    USE SIGNAL ;
    SHAPE ABUTMENT ;
    PORT
      LAYER met3 ;
      RECT 0.000 241.050 0.800 241.350 ;
    END
  END wd_in[39]
  PIN wd_in[40]
    DIRECTION INPUT ;
    USE SIGNAL ;
    SHAPE ABUTMENT ;
    PORT
      LAYER met3 ;
      RECT 0.000 242.250 0.800 242.550 ;
    END
  END wd_in[40]
  PIN wd_in[41]
    DIRECTION INPUT ;
    USE SIGNAL ;
    SHAPE ABUTMENT ;
    PORT
      LAYER met3 ;
      RECT 0.000 243.450 0.800 243.750 ;
    END
  END wd_in[41]
  PIN wd_in[42]
    DIRECTION INPUT ;
    USE SIGNAL ;
    SHAPE ABUTMENT ;
    PORT
      LAYER met3 ;
      RECT 0.000 244.650 0.800 244.950 ;
    END
  END wd_in[42]
  PIN wd_in[43]
    DIRECTION INPUT ;
    USE SIGNAL ;
    SHAPE ABUTMENT ;
    PORT
      LAYER met3 ;
      RECT 0.000 245.850 0.800 246.150 ;
    END
  END wd_in[43]
  PIN wd_in[44]
    DIRECTION INPUT ;
    USE SIGNAL ;
    SHAPE ABUTMENT ;
    PORT
      LAYER met3 ;
      RECT 0.000 247.050 0.800 247.350 ;
    END
  END wd_in[44]
  PIN wd_in[45]
    DIRECTION INPUT ;
    USE SIGNAL ;
    SHAPE ABUTMENT ;
    PORT
      LAYER met3 ;
      RECT 0.000 248.250 0.800 248.550 ;
    END
  END wd_in[45]
  PIN wd_in[46]
    DIRECTION INPUT ;
    USE SIGNAL ;
    SHAPE ABUTMENT ;
    PORT
      LAYER met3 ;
      RECT 0.000 249.450 0.800 249.750 ;
    END
  END wd_in[46]
  PIN wd_in[47]
    DIRECTION INPUT ;
    USE SIGNAL ;
    SHAPE ABUTMENT ;
    PORT
      LAYER met3 ;
      RECT 0.000 250.650 0.800 250.950 ;
    END
  END wd_in[47]
  PIN wd_in[48]
    DIRECTION INPUT ;
    USE SIGNAL ;
    SHAPE ABUTMENT ;
    PORT
      LAYER met3 ;
      RECT 0.000 251.850 0.800 252.150 ;
    END
  END wd_in[48]
  PIN wd_in[49]
    DIRECTION INPUT ;
    USE SIGNAL ;
    SHAPE ABUTMENT ;
    PORT
      LAYER met3 ;
      RECT 0.000 253.050 0.800 253.350 ;
    END
  END wd_in[49]
  PIN wd_in[50]
    DIRECTION INPUT ;
    USE SIGNAL ;
    SHAPE ABUTMENT ;
    PORT
      LAYER met3 ;
      RECT 0.000 254.250 0.800 254.550 ;
    END
  END wd_in[50]
  PIN wd_in[51]
    DIRECTION INPUT ;
    USE SIGNAL ;
    SHAPE ABUTMENT ;
    PORT
      LAYER met3 ;
      RECT 0.000 255.450 0.800 255.750 ;
    END
  END wd_in[51]
  PIN wd_in[52]
    DIRECTION INPUT ;
    USE SIGNAL ;
    SHAPE ABUTMENT ;
    PORT
      LAYER met3 ;
      RECT 0.000 256.650 0.800 256.950 ;
    END
  END wd_in[52]
  PIN wd_in[53]
    DIRECTION INPUT ;
    USE SIGNAL ;
    SHAPE ABUTMENT ;
    PORT
      LAYER met3 ;
      RECT 0.000 257.850 0.800 258.150 ;
    END
  END wd_in[53]
  PIN wd_in[54]
    DIRECTION INPUT ;
    USE SIGNAL ;
    SHAPE ABUTMENT ;
    PORT
      LAYER met3 ;
      RECT 0.000 259.050 0.800 259.350 ;
    END
  END wd_in[54]
  PIN wd_in[55]
    DIRECTION INPUT ;
    USE SIGNAL ;
    SHAPE ABUTMENT ;
    PORT
      LAYER met3 ;
      RECT 0.000 260.250 0.800 260.550 ;
    END
  END wd_in[55]
  PIN wd_in[56]
    DIRECTION INPUT ;
    USE SIGNAL ;
    SHAPE ABUTMENT ;
    PORT
      LAYER met3 ;
      RECT 0.000 261.450 0.800 261.750 ;
    END
  END wd_in[56]
  PIN wd_in[57]
    DIRECTION INPUT ;
    USE SIGNAL ;
    SHAPE ABUTMENT ;
    PORT
      LAYER met3 ;
      RECT 0.000 262.650 0.800 262.950 ;
    END
  END wd_in[57]
  PIN wd_in[58]
    DIRECTION INPUT ;
    USE SIGNAL ;
    SHAPE ABUTMENT ;
    PORT
      LAYER met3 ;
      RECT 0.000 263.850 0.800 264.150 ;
    END
  END wd_in[58]
  PIN wd_in[59]
    DIRECTION INPUT ;
    USE SIGNAL ;
    SHAPE ABUTMENT ;
    PORT
      LAYER met3 ;
      RECT 0.000 265.050 0.800 265.350 ;
    END
  END wd_in[59]
  PIN wd_in[60]
    DIRECTION INPUT ;
    USE SIGNAL ;
    SHAPE ABUTMENT ;
    PORT
      LAYER met3 ;
      RECT 0.000 266.250 0.800 266.550 ;
    END
  END wd_in[60]
  PIN wd_in[61]
    DIRECTION INPUT ;
    USE SIGNAL ;
    SHAPE ABUTMENT ;
    PORT
      LAYER met3 ;
      RECT 0.000 267.450 0.800 267.750 ;
    END
  END wd_in[61]
  PIN wd_in[62]
    DIRECTION INPUT ;
    USE SIGNAL ;
    SHAPE ABUTMENT ;
    PORT
      LAYER met3 ;
      RECT 0.000 268.650 0.800 268.950 ;
    END
  END wd_in[62]
  PIN wd_in[63]
    DIRECTION INPUT ;
    USE SIGNAL ;
    SHAPE ABUTMENT ;
    PORT
      LAYER met3 ;
      RECT 0.000 269.850 0.800 270.150 ;
    END
  END wd_in[63]
  PIN addr_in[0]
    DIRECTION INPUT ;
    USE SIGNAL ;
    SHAPE ABUTMENT ;
    PORT
      LAYER met3 ;
      RECT 0.000 288.450 0.800 288.750 ;
    END
  END addr_in[0]
  PIN addr_in[1]
    DIRECTION INPUT ;
    USE SIGNAL ;
    SHAPE ABUTMENT ;
    PORT
      LAYER met3 ;
      RECT 0.000 289.650 0.800 289.950 ;
    END
  END addr_in[1]
  PIN addr_in[2]
    DIRECTION INPUT ;
    USE SIGNAL ;
    SHAPE ABUTMENT ;
    PORT
      LAYER met3 ;
      RECT 0.000 290.850 0.800 291.150 ;
    END
  END addr_in[2]
  PIN addr_in[3]
    DIRECTION INPUT ;
    USE SIGNAL ;
    SHAPE ABUTMENT ;
    PORT
      LAYER met3 ;
      RECT 0.000 292.050 0.800 292.350 ;
    END
  END addr_in[3]
  PIN addr_in[4]
    DIRECTION INPUT ;
    USE SIGNAL ;
    SHAPE ABUTMENT ;
    PORT
      LAYER met3 ;
      RECT 0.000 293.250 0.800 293.550 ;
    END
  END addr_in[4]
  PIN addr_in[5]
    DIRECTION INPUT ;
    USE SIGNAL ;
    SHAPE ABUTMENT ;
    PORT
      LAYER met3 ;
      RECT 0.000 294.450 0.800 294.750 ;
    END
  END addr_in[5]
  PIN addr_in[6]
    DIRECTION INPUT ;
    USE SIGNAL ;
    SHAPE ABUTMENT ;
    PORT
      LAYER met3 ;
      RECT 0.000 295.650 0.800 295.950 ;
    END
  END addr_in[6]
  PIN we_in
    DIRECTION INPUT ;
    USE SIGNAL ;
    SHAPE ABUTMENT ;
    PORT
      LAYER met3 ;
      RECT 0.000 314.250 0.800 314.550 ;
    END
  END we_in
  PIN ce_in
    DIRECTION INPUT ;
    USE SIGNAL ;
    SHAPE ABUTMENT ;
    PORT
      LAYER met3 ;
      RECT 0.000 315.450 0.800 315.750 ;
    END
  END ce_in
  PIN clk
    DIRECTION INPUT ;
    USE SIGNAL ;
    SHAPE ABUTMENT ;
    PORT
      LAYER met3 ;
      RECT 0.000 316.650 0.800 316.950 ;
    END
  END clk
  PIN VSS
    DIRECTION INOUT ;
    USE GROUND ;
    PORT
      LAYER met4 ;
      RECT 5.400 6.000 6.600 323.120 ;
      RECT 15.000 6.000 16.200 323.120 ;
      RECT 24.600 6.000 25.800 323.120 ;
      RECT 34.200 6.000 35.400 323.120 ;
      RECT 43.800 6.000 45.000 323.120 ;
      RECT 53.400 6.000 54.600 323.120 ;
      RECT 63.000 6.000 64.200 323.120 ;
      RECT 72.600 6.000 73.800 323.120 ;
      RECT 82.200 6.000 83.400 323.120 ;
      RECT 91.800 6.000 93.000 323.120 ;
      RECT 101.400 6.000 102.600 323.120 ;
      RECT 111.000 6.000 112.200 323.120 ;
      RECT 120.600 6.000 121.800 323.120 ;
      RECT 130.200 6.000 131.400 323.120 ;
      RECT 139.800 6.000 141.000 323.120 ;
      RECT 149.400 6.000 150.600 323.120 ;
      RECT 159.000 6.000 160.200 323.120 ;
      RECT 168.600 6.000 169.800 323.120 ;
      RECT 178.200 6.000 179.400 323.120 ;
    END
  END VSS
  PIN VDD
    DIRECTION INOUT ;
    USE POWER ;
    PORT
      LAYER met4 ;
      RECT 10.200 6.000 11.400 323.120 ;
      RECT 19.800 6.000 21.000 323.120 ;
      RECT 29.400 6.000 30.600 323.120 ;
      RECT 39.000 6.000 40.200 323.120 ;
      RECT 48.600 6.000 49.800 323.120 ;
      RECT 58.200 6.000 59.400 323.120 ;
      RECT 67.800 6.000 69.000 323.120 ;
      RECT 77.400 6.000 78.600 323.120 ;
      RECT 87.000 6.000 88.200 323.120 ;
      RECT 96.600 6.000 97.800 323.120 ;
      RECT 106.200 6.000 107.400 323.120 ;
      RECT 115.800 6.000 117.000 323.120 ;
      RECT 125.400 6.000 126.600 323.120 ;
      RECT 135.000 6.000 136.200 323.120 ;
      RECT 144.600 6.000 145.800 323.120 ;
      RECT 154.200 6.000 155.400 323.120 ;
      RECT 163.800 6.000 165.000 323.120 ;
      RECT 173.400 6.000 174.600 323.120 ;
      RECT 183.000 6.000 184.200 323.120 ;
    END
  END VDD
  OBS
    LAYER met1 ;
    RECT 0 0 191.820 329.120 ;
    LAYER met2 ;
    RECT 0 0 191.820 329.120 ;
    LAYER met3 ;
    RECT 0.800 0 191.820 329.120 ;
    RECT 0 0.000 0.800 5.850 ;
    RECT 0 6.150 0.800 7.050 ;
    RECT 0 7.350 0.800 8.250 ;
    RECT 0 8.550 0.800 9.450 ;
    RECT 0 9.750 0.800 10.650 ;
    RECT 0 10.950 0.800 11.850 ;
    RECT 0 12.150 0.800 13.050 ;
    RECT 0 13.350 0.800 14.250 ;
    RECT 0 14.550 0.800 15.450 ;
    RECT 0 15.750 0.800 16.650 ;
    RECT 0 16.950 0.800 17.850 ;
    RECT 0 18.150 0.800 19.050 ;
    RECT 0 19.350 0.800 20.250 ;
    RECT 0 20.550 0.800 21.450 ;
    RECT 0 21.750 0.800 22.650 ;
    RECT 0 22.950 0.800 23.850 ;
    RECT 0 24.150 0.800 25.050 ;
    RECT 0 25.350 0.800 26.250 ;
    RECT 0 26.550 0.800 27.450 ;
    RECT 0 27.750 0.800 28.650 ;
    RECT 0 28.950 0.800 29.850 ;
    RECT 0 30.150 0.800 31.050 ;
    RECT 0 31.350 0.800 32.250 ;
    RECT 0 32.550 0.800 33.450 ;
    RECT 0 33.750 0.800 34.650 ;
    RECT 0 34.950 0.800 35.850 ;
    RECT 0 36.150 0.800 37.050 ;
    RECT 0 37.350 0.800 38.250 ;
    RECT 0 38.550 0.800 39.450 ;
    RECT 0 39.750 0.800 40.650 ;
    RECT 0 40.950 0.800 41.850 ;
    RECT 0 42.150 0.800 43.050 ;
    RECT 0 43.350 0.800 44.250 ;
    RECT 0 44.550 0.800 45.450 ;
    RECT 0 45.750 0.800 46.650 ;
    RECT 0 46.950 0.800 47.850 ;
    RECT 0 48.150 0.800 49.050 ;
    RECT 0 49.350 0.800 50.250 ;
    RECT 0 50.550 0.800 51.450 ;
    RECT 0 51.750 0.800 52.650 ;
    RECT 0 52.950 0.800 53.850 ;
    RECT 0 54.150 0.800 55.050 ;
    RECT 0 55.350 0.800 56.250 ;
    RECT 0 56.550 0.800 57.450 ;
    RECT 0 57.750 0.800 58.650 ;
    RECT 0 58.950 0.800 59.850 ;
    RECT 0 60.150 0.800 61.050 ;
    RECT 0 61.350 0.800 62.250 ;
    RECT 0 62.550 0.800 63.450 ;
    RECT 0 63.750 0.800 64.650 ;
    RECT 0 64.950 0.800 65.850 ;
    RECT 0 66.150 0.800 67.050 ;
    RECT 0 67.350 0.800 68.250 ;
    RECT 0 68.550 0.800 69.450 ;
    RECT 0 69.750 0.800 70.650 ;
    RECT 0 70.950 0.800 71.850 ;
    RECT 0 72.150 0.800 73.050 ;
    RECT 0 73.350 0.800 74.250 ;
    RECT 0 74.550 0.800 75.450 ;
    RECT 0 75.750 0.800 76.650 ;
    RECT 0 76.950 0.800 77.850 ;
    RECT 0 78.150 0.800 79.050 ;
    RECT 0 79.350 0.800 80.250 ;
    RECT 0 80.550 0.800 81.450 ;
    RECT 0 81.750 0.800 100.050 ;
    RECT 0 100.350 0.800 101.250 ;
    RECT 0 101.550 0.800 102.450 ;
    RECT 0 102.750 0.800 103.650 ;
    RECT 0 103.950 0.800 104.850 ;
    RECT 0 105.150 0.800 106.050 ;
    RECT 0 106.350 0.800 107.250 ;
    RECT 0 107.550 0.800 108.450 ;
    RECT 0 108.750 0.800 109.650 ;
    RECT 0 109.950 0.800 110.850 ;
    RECT 0 111.150 0.800 112.050 ;
    RECT 0 112.350 0.800 113.250 ;
    RECT 0 113.550 0.800 114.450 ;
    RECT 0 114.750 0.800 115.650 ;
    RECT 0 115.950 0.800 116.850 ;
    RECT 0 117.150 0.800 118.050 ;
    RECT 0 118.350 0.800 119.250 ;
    RECT 0 119.550 0.800 120.450 ;
    RECT 0 120.750 0.800 121.650 ;
    RECT 0 121.950 0.800 122.850 ;
    RECT 0 123.150 0.800 124.050 ;
    RECT 0 124.350 0.800 125.250 ;
    RECT 0 125.550 0.800 126.450 ;
    RECT 0 126.750 0.800 127.650 ;
    RECT 0 127.950 0.800 128.850 ;
    RECT 0 129.150 0.800 130.050 ;
    RECT 0 130.350 0.800 131.250 ;
    RECT 0 131.550 0.800 132.450 ;
    RECT 0 132.750 0.800 133.650 ;
    RECT 0 133.950 0.800 134.850 ;
    RECT 0 135.150 0.800 136.050 ;
    RECT 0 136.350 0.800 137.250 ;
    RECT 0 137.550 0.800 138.450 ;
    RECT 0 138.750 0.800 139.650 ;
    RECT 0 139.950 0.800 140.850 ;
    RECT 0 141.150 0.800 142.050 ;
    RECT 0 142.350 0.800 143.250 ;
    RECT 0 143.550 0.800 144.450 ;
    RECT 0 144.750 0.800 145.650 ;
    RECT 0 145.950 0.800 146.850 ;
    RECT 0 147.150 0.800 148.050 ;
    RECT 0 148.350 0.800 149.250 ;
    RECT 0 149.550 0.800 150.450 ;
    RECT 0 150.750 0.800 151.650 ;
    RECT 0 151.950 0.800 152.850 ;
    RECT 0 153.150 0.800 154.050 ;
    RECT 0 154.350 0.800 155.250 ;
    RECT 0 155.550 0.800 156.450 ;
    RECT 0 156.750 0.800 157.650 ;
    RECT 0 157.950 0.800 158.850 ;
    RECT 0 159.150 0.800 160.050 ;
    RECT 0 160.350 0.800 161.250 ;
    RECT 0 161.550 0.800 162.450 ;
    RECT 0 162.750 0.800 163.650 ;
    RECT 0 163.950 0.800 164.850 ;
    RECT 0 165.150 0.800 166.050 ;
    RECT 0 166.350 0.800 167.250 ;
    RECT 0 167.550 0.800 168.450 ;
    RECT 0 168.750 0.800 169.650 ;
    RECT 0 169.950 0.800 170.850 ;
    RECT 0 171.150 0.800 172.050 ;
    RECT 0 172.350 0.800 173.250 ;
    RECT 0 173.550 0.800 174.450 ;
    RECT 0 174.750 0.800 175.650 ;
    RECT 0 175.950 0.800 194.250 ;
    RECT 0 194.550 0.800 195.450 ;
    RECT 0 195.750 0.800 196.650 ;
    RECT 0 196.950 0.800 197.850 ;
    RECT 0 198.150 0.800 199.050 ;
    RECT 0 199.350 0.800 200.250 ;
    RECT 0 200.550 0.800 201.450 ;
    RECT 0 201.750 0.800 202.650 ;
    RECT 0 202.950 0.800 203.850 ;
    RECT 0 204.150 0.800 205.050 ;
    RECT 0 205.350 0.800 206.250 ;
    RECT 0 206.550 0.800 207.450 ;
    RECT 0 207.750 0.800 208.650 ;
    RECT 0 208.950 0.800 209.850 ;
    RECT 0 210.150 0.800 211.050 ;
    RECT 0 211.350 0.800 212.250 ;
    RECT 0 212.550 0.800 213.450 ;
    RECT 0 213.750 0.800 214.650 ;
    RECT 0 214.950 0.800 215.850 ;
    RECT 0 216.150 0.800 217.050 ;
    RECT 0 217.350 0.800 218.250 ;
    RECT 0 218.550 0.800 219.450 ;
    RECT 0 219.750 0.800 220.650 ;
    RECT 0 220.950 0.800 221.850 ;
    RECT 0 222.150 0.800 223.050 ;
    RECT 0 223.350 0.800 224.250 ;
    RECT 0 224.550 0.800 225.450 ;
    RECT 0 225.750 0.800 226.650 ;
    RECT 0 226.950 0.800 227.850 ;
    RECT 0 228.150 0.800 229.050 ;
    RECT 0 229.350 0.800 230.250 ;
    RECT 0 230.550 0.800 231.450 ;
    RECT 0 231.750 0.800 232.650 ;
    RECT 0 232.950 0.800 233.850 ;
    RECT 0 234.150 0.800 235.050 ;
    RECT 0 235.350 0.800 236.250 ;
    RECT 0 236.550 0.800 237.450 ;
    RECT 0 237.750 0.800 238.650 ;
    RECT 0 238.950 0.800 239.850 ;
    RECT 0 240.150 0.800 241.050 ;
    RECT 0 241.350 0.800 242.250 ;
    RECT 0 242.550 0.800 243.450 ;
    RECT 0 243.750 0.800 244.650 ;
    RECT 0 244.950 0.800 245.850 ;
    RECT 0 246.150 0.800 247.050 ;
    RECT 0 247.350 0.800 248.250 ;
    RECT 0 248.550 0.800 249.450 ;
    RECT 0 249.750 0.800 250.650 ;
    RECT 0 250.950 0.800 251.850 ;
    RECT 0 252.150 0.800 253.050 ;
    RECT 0 253.350 0.800 254.250 ;
    RECT 0 254.550 0.800 255.450 ;
    RECT 0 255.750 0.800 256.650 ;
    RECT 0 256.950 0.800 257.850 ;
    RECT 0 258.150 0.800 259.050 ;
    RECT 0 259.350 0.800 260.250 ;
    RECT 0 260.550 0.800 261.450 ;
    RECT 0 261.750 0.800 262.650 ;
    RECT 0 262.950 0.800 263.850 ;
    RECT 0 264.150 0.800 265.050 ;
    RECT 0 265.350 0.800 266.250 ;
    RECT 0 266.550 0.800 267.450 ;
    RECT 0 267.750 0.800 268.650 ;
    RECT 0 268.950 0.800 269.850 ;
    RECT 0 270.150 0.800 288.450 ;
    RECT 0 288.750 0.800 289.650 ;
    RECT 0 289.950 0.800 290.850 ;
    RECT 0 291.150 0.800 292.050 ;
    RECT 0 292.350 0.800 293.250 ;
    RECT 0 293.550 0.800 294.450 ;
    RECT 0 294.750 0.800 295.650 ;
    RECT 0 295.950 0.800 314.250 ;
    RECT 0 314.550 0.800 315.450 ;
    RECT 0 315.750 0.800 316.650 ;
    RECT 0 316.950 0.800 329.120 ;
    LAYER met4 ;
    RECT 0 0 191.820 6.000 ;
    RECT 0 323.120 191.820 329.120 ;
    RECT 0.000 6.000 5.400 323.120 ;
    RECT 6.600 6.000 10.200 323.120 ;
    RECT 11.400 6.000 15.000 323.120 ;
    RECT 16.200 6.000 19.800 323.120 ;
    RECT 21.000 6.000 24.600 323.120 ;
    RECT 25.800 6.000 29.400 323.120 ;
    RECT 30.600 6.000 34.200 323.120 ;
    RECT 35.400 6.000 39.000 323.120 ;
    RECT 40.200 6.000 43.800 323.120 ;
    RECT 45.000 6.000 48.600 323.120 ;
    RECT 49.800 6.000 53.400 323.120 ;
    RECT 54.600 6.000 58.200 323.120 ;
    RECT 59.400 6.000 63.000 323.120 ;
    RECT 64.200 6.000 67.800 323.120 ;
    RECT 69.000 6.000 72.600 323.120 ;
    RECT 73.800 6.000 77.400 323.120 ;
    RECT 78.600 6.000 82.200 323.120 ;
    RECT 83.400 6.000 87.000 323.120 ;
    RECT 88.200 6.000 91.800 323.120 ;
    RECT 93.000 6.000 96.600 323.120 ;
    RECT 97.800 6.000 101.400 323.120 ;
    RECT 102.600 6.000 106.200 323.120 ;
    RECT 107.400 6.000 111.000 323.120 ;
    RECT 112.200 6.000 115.800 323.120 ;
    RECT 117.000 6.000 120.600 323.120 ;
    RECT 121.800 6.000 125.400 323.120 ;
    RECT 126.600 6.000 130.200 323.120 ;
    RECT 131.400 6.000 135.000 323.120 ;
    RECT 136.200 6.000 139.800 323.120 ;
    RECT 141.000 6.000 144.600 323.120 ;
    RECT 145.800 6.000 149.400 323.120 ;
    RECT 150.600 6.000 154.200 323.120 ;
    RECT 155.400 6.000 159.000 323.120 ;
    RECT 160.200 6.000 163.800 323.120 ;
    RECT 165.000 6.000 168.600 323.120 ;
    RECT 169.800 6.000 173.400 323.120 ;
    RECT 174.600 6.000 178.200 323.120 ;
    RECT 179.400 6.000 183.000 323.120 ;
    RECT 184.200 6.000 191.820 323.120 ;
    LAYER OVERLAP ;
    RECT 0 0 191.820 329.120 ;
  END
END fakeram130_128x64

END LIBRARY
